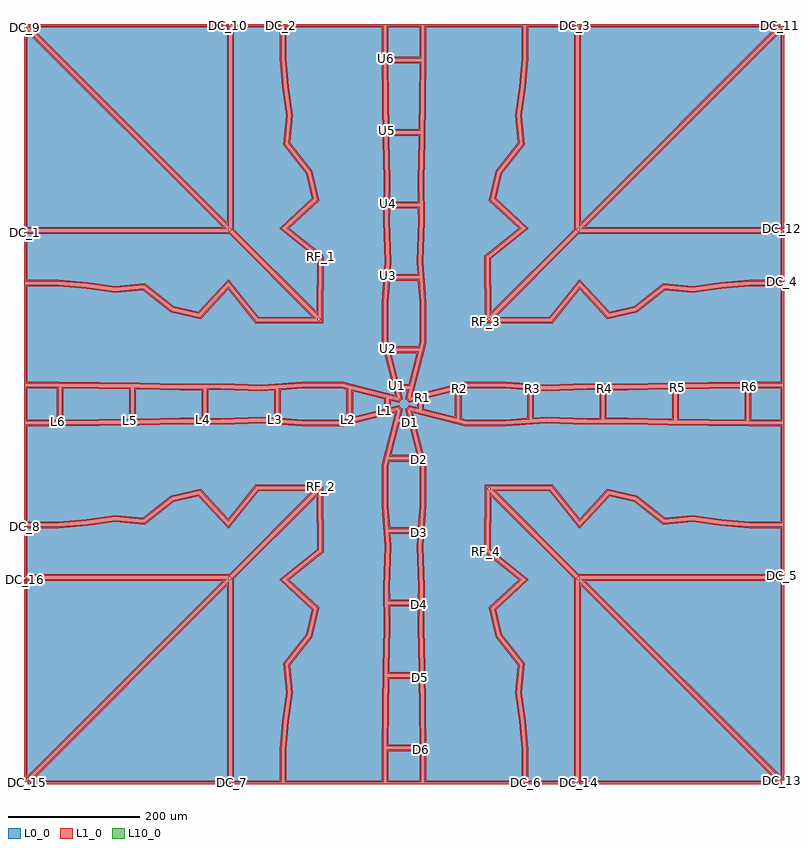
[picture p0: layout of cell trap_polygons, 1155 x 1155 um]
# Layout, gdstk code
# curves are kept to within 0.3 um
import gdstk
lib = gdstk.Library(unit=1e-6, precision=1e-09)
def P(c, l, *ps):  # polygons
    for p in ps: c.add(gdstk.Polygon(p, *l))
L0_0 = (0, 0)
L1_0 = (1, 0)
L10_0 = (10, 0)

trap_polygons = lib.new_cell('trap_polygons')
P(trap_polygons, L0_0, [(-575,-266.125),(-269.661,-266.125),(-575,-571.464),(-575,-266.125)],
  [(-571.464,-575),(-266.125,-269.661),(-266.125,-575),(-571.464,-575)],
  [(266.125,-575),(266.125,-269.661),(571.464,-575),(266.125,-575)],
  [(575,-571.464),(269.661,-266.125),(575,-266.125),(575,-571.464)],
  [(575,266.125),(269.661,266.125),(575,571.464),(575,266.125)],
  [(571.464,575),(266.125,269.661),(266.125,575),(571.464,575)],
  [(-266.125,575),(-266.125,269.661),(-571.464,575),(-266.125,575)],
  [(-575,571.464),(-269.661,266.125),(-575,266.125),(-575,571.464)],
  [(-575,-186.125),(-524.788,-186.125),(-481.472,-182.439),(-438.926,-176.757),(-394.504,-180.815),(-350.84,-146.071),(-311.781,-137.162),(-266.827,-185.634),(-221.734,-129.646),(-133.964,-130.428),(-264.661,-261.125),(-575,-261.125)],
  [(-261.125,-575),(-261.125,-264.661),(-130.428,-133.964),(-129.646,-221.734),(-185.634,-266.827),(-137.162,-311.781),(-146.071,-350.84),(-180.815,-394.504),(-176.757,-438.926),(-182.439,-481.472),(-186.125,-524.788),(-186.125,-575)],
  [(186.125,-575),(186.125,-524.788),(182.439,-481.472),(176.757,-438.926),(180.815,-394.504),(146.071,-350.84),(137.162,-311.781),(185.634,-266.827),(129.646,-221.734),(130.428,-133.964),(261.125,-264.661),(261.125,-575)],
  [(575,-261.125),(264.661,-261.125),(133.964,-130.428),(221.734,-129.646),(266.827,-185.634),(311.781,-137.162),(350.84,-146.071),(394.504,-180.815),(438.926,-176.757),(481.472,-182.439),(524.788,-186.125),(575,-186.125)],
  [(575,186.125),(524.788,186.125),(481.472,182.439),(438.926,176.757),(394.504,180.815),(350.84,146.071),(311.781,137.162),(266.827,185.634),(221.734,129.646),(133.964,130.428),(264.661,261.125),(575,261.125)],
  [(261.125,575),(261.125,264.661),(130.428,133.964),(129.646,221.734),(185.634,266.827),(137.162,311.781),(146.071,350.84),(180.815,394.504),(176.757,438.926),(182.439,481.472),(186.125,524.788),(186.125,575)],
  [(-186.125,575),(-186.125,524.788),(-182.439,481.472),(-176.757,438.926),(-180.815,394.504),(-146.071,350.84),(-137.162,311.781),(-185.634,266.827),(-129.646,221.734),(-130.428,133.964),(-261.125,264.661),(-261.125,575)],
  [(-575,261.125),(-264.661,261.125),(-133.964,130.428),(-221.734,129.646),(-266.827,185.634),(-311.781,137.162),(-350.84,146.071),(-394.504,180.815),(-438.926,176.757),(-481.472,182.439),(-524.788,186.125),(-575,186.125)],
  [(-26.125,525),(-26.125,575),(26.125,575),(26.125,525),(-26.125,525)],
  [(525,26.125),(575,26.125),(575,-26.125),(525,-26.125),(525,26.125)],
  [(26.125,-525),(26.125,-575),(-26.125,-575),(-26.125,-525),(26.125,-525)],
  [(-525,-26.125),(-575,-26.125),(-575,26.125),(-525,26.125),(-525,-26.125)],
  [(-24.813,415),(-25.435,463.528),(-26.125,520),(26.125,520),(25.435,463.528),(24.813,415),(-24.813,415)],
  [(415,24.813),(463.528,25.435),(520,26.125),(520,-26.125),(463.528,-25.435),(415,-24.813),(415,24.813)],
  [(24.813,-415),(25.435,-463.528),(26.125,-520),(-26.125,-520),(-25.435,-463.528),(-24.813,-415),(24.813,-415)],
  [(-415,-24.813),(-463.528,-25.435),(-520,-26.125),(-520,26.125),(-463.528,25.435),(-415,24.813),(-415,-24.813)],
  [(-23.661,305),(-23.354,339.827),(-24.641,401.615),(-24.749,410),(24.749,410),(24.641,401.615),(23.354,339.827),(23.661,305),(-23.661,305)],
  [(305,23.661),(339.827,23.354),(401.615,24.641),(410,24.749),(410,-24.749),(401.615,-24.641),(339.827,-23.354),(305,-23.661),(305,23.661)],
  [(23.661,-305),(23.354,-339.827),(24.641,-401.615),(24.749,-410),(-24.749,-410),(-24.641,-401.615),(-23.354,-339.827),(-23.661,-305),(23.661,-305)],
  [(-305,-23.661),(-339.827,-23.354),(-401.615,-24.641),(-410,-24.749),(-410,24.749),(-401.615,24.641),(-339.827,23.354),(-305,23.661),(-305,-23.661)],
  [(-23.237,195),(-21.725,216.238),(-23.897,278.128),(-23.705,300),(23.705,300),(23.897,278.128),(21.725,216.238),(23.237,195),(-23.237,195)],
  [(195,23.237),(216.238,21.725),(278.128,23.897),(300,23.705),(300,-23.705),(278.128,-23.897),(216.238,-21.725),(195,-23.237),(195,23.237)],
  [(23.237,-195),(21.725,-216.238),(23.897,-278.128),(23.705,-300),(-23.705,-300),(-23.897,-278.128),(-21.725,-216.238),(-23.237,-195),(23.237,-195)],
  [(-195,-23.237),(-216.238,-21.725),(-278.128,-23.897),(-300,-23.705),(-300,23.705),(-278.128,23.897),(-216.238,21.725),(-195,23.237),(-195,-23.237)],
  [(-23.931,85),(-26.091,93.487),(-26.125,154.417),(-23.592,190),(23.592,190),(26.125,154.417),(26.091,93.487),(23.931,85),(-23.931,85)],
  [(85,23.931),(93.487,26.091),(154.417,26.125),(190,23.592),(190,-23.592),(154.417,-26.125),(93.487,-26.091),(85,-23.931),(85,23.931)],
  [(23.931,-85),(26.091,-93.487),(26.125,-154.417),(23.592,-190),(-23.592,-190),(-26.125,-154.417),(-26.091,-93.487),(-23.931,-85),(23.931,-85)],
  [(-85,-23.931),(-93.487,-26.091),(-154.417,-26.125),(-190,-23.592),(-190,23.592),(-154.417,26.125),(-93.487,26.091),(-85,23.931),(-85,-23.931)],
  [(-9.299,27.5),(-22.659,80),(22.659,80),(9.299,27.5),(-9.299,27.5)],
  [(27.5,9.299),(80,22.659),(80,-22.659),(27.5,-9.299),(27.5,9.299)],
  [(9.299,-27.5),(22.659,-80),(-22.659,-80),(-9.299,-27.5),(9.299,-27.5)],
  [(-27.5,-9.299),(-80,-22.659),(-80,22.659),(-27.5,9.299),(-27.5,-9.299)],
  [(8.315,-5.556),(6.344,-7.73),(4.563,-8.89),(8.027,-22.5),(-8.027,-22.5),(-4.563,-8.89),(-7.071,-7.071),(-8.89,-4.563),(-22.5,-8.027),(-22.5,8.027),(-8.89,4.563),(-7.071,7.071),(-4.563,8.89),(-8.027,22.5),(8.027,22.5),(4.563,8.89),(7.071,7.071),(8.89,4.563),(22.5,8.027),(22.5,-8.027),(8.89,-4.563)],
  [(124.625,-224.109),(177.993,-267.094),(131.645,-310.078),(141.449,-353.062),(175.653,-396.047),(171.727,-439.031),(177.467,-482.016),(181.125,-525),(181.125,-575),(31.125,-575),(31.125,-525),(30.432,-463.266),(28.355,-339.797),(28.898,-278.062),(26.731,-216.328),(31.125,-154.594),(31.091,-92.859),(10.007,-10.007),(92.859,-31.091),(154.594,-31.125),(216.328,-26.731),(278.062,-28.898),(339.797,-28.355),(463.266,-30.432),(525,-31.125),(575,-31.125),(575,-181.125),(525,-181.125),(482.016,-177.467),(439.031,-171.727),(396.047,-175.653),(353.062,-141.449),(310.078,-131.645),(267.094,-177.993),(224.109,-124.625),(125.504,-125.504)],
  [(125.504,125.504),(224.109,124.625),(267.094,177.993),(310.078,131.645),(353.062,141.449),(396.047,175.653),(439.031,171.727),(482.016,177.467),(525,181.125),(575,181.125),(575,31.125),(525,31.125),(463.266,30.432),(339.797,28.355),(278.062,28.898),(216.328,26.731),(154.594,31.125),(92.859,31.091),(10.007,10.007),(31.091,92.859),(31.125,154.594),(26.731,216.328),(28.898,278.062),(28.355,339.797),(30.432,463.266),(31.125,525),(31.125,575),(181.125,575),(181.125,525),(177.467,482.016),(171.727,439.031),(175.653,396.047),(141.449,353.062),(131.645,310.078),(177.993,267.094),(124.625,224.109)],
  [(-125.504,-125.504),(-224.109,-124.625),(-267.094,-177.993),(-310.078,-131.645),(-353.062,-141.449),(-396.047,-175.653),(-439.031,-171.727),(-482.016,-177.467),(-525,-181.125),(-575,-181.125),(-575,-31.125),(-525,-31.125),(-463.266,-30.432),(-339.797,-28.355),(-278.062,-28.898),(-216.328,-26.731),(-154.594,-31.125),(-92.859,-31.091),(-10.007,-10.007),(-31.091,-92.859),(-31.125,-154.594),(-26.731,-216.328),(-28.898,-278.062),(-28.355,-339.797),(-30.432,-463.266),(-31.125,-525),(-31.125,-575),(-181.125,-575),(-181.125,-525),(-177.467,-482.016),(-171.727,-439.031),(-175.653,-396.047),(-141.449,-353.062),(-131.645,-310.078),(-177.993,-267.094),(-124.625,-224.109)],
  [(-124.625,224.109),(-177.993,267.094),(-131.645,310.078),(-141.449,353.062),(-175.653,396.047),(-171.727,439.031),(-177.467,482.016),(-181.125,525),(-181.125,575),(-31.125,575),(-31.125,525),(-30.432,463.266),(-28.355,339.797),(-28.898,278.062),(-26.731,216.328),(-31.125,154.594),(-31.091,92.859),(-10.007,10.007),(-92.859,31.091),(-154.594,31.125),(-216.328,26.731),(-278.062,28.898),(-339.797,28.355),(-463.266,30.432),(-525,31.125),(-575,31.125),(-575,181.125),(-525,181.125),(-482.016,177.467),(-439.031,171.727),(-396.047,175.653),(-353.062,141.449),(-310.078,131.645),(-267.094,177.993),(-224.109,124.625),(-125.504,125.504)])
P(trap_polygons, L1_0, [(-575,-263.625),(-575,-268.625),(-275.696,-268.625),(-572.5,-565.429),(-572.5,-266.125),(-577.5,-266.125),(-577.5,-573.964),(-575,-575),(-266.125,-266.125),(-267.161,-263.625)],
  [(-573.232,-573.232),(-569.697,-576.768),(-268.625,-275.696),(-268.625,-572.5),(-571.464,-572.5),(-571.464,-577.5),(-263.625,-577.5),(-263.625,-267.161),(-266.125,-266.125)],
  [(263.625,-575),(268.625,-575),(268.625,-275.696),(565.429,-572.5),(266.125,-572.5),(266.125,-577.5),(573.964,-577.5),(575,-575),(266.125,-266.125),(263.625,-267.161)],
  [(573.232,-573.232),(576.768,-569.697),(275.696,-268.625),(572.5,-268.625),(572.5,-571.464),(577.5,-571.464),(577.5,-263.625),(267.161,-263.625),(266.125,-266.125)],
  [(575,263.625),(575,268.625),(275.696,268.625),(572.5,565.429),(572.5,266.125),(577.5,266.125),(577.5,573.964),(575,575),(266.125,266.125),(267.161,263.625)],
  [(573.232,573.232),(569.697,576.768),(268.625,275.696),(268.625,572.5),(571.464,572.5),(571.464,577.5),(263.625,577.5),(263.625,267.161),(266.125,266.125)],
  [(-263.625,575),(-268.625,575),(-268.625,275.696),(-565.429,572.5),(-266.125,572.5),(-266.125,577.5),(-573.964,577.5),(-575,575),(-266.125,266.125),(-263.625,267.161)],
  [(-573.232,573.232),(-576.768,569.697),(-275.696,268.625),(-572.5,268.625),(-572.5,571.464),(-577.5,571.464),(-577.5,263.625),(-267.161,263.625),(-266.125,266.125)],
  [(-575,-183.625),(-575,-188.625),(-524.681,-188.625),(-481.201,-184.925),(-438.874,-179.272),(-393.732,-183.396),(-349.729,-148.381),(-312.632,-139.92),(-266.96,-189.167),(-266.448,-189.149),(-220.546,-132.157),(-139.946,-132.875),(-265.696,-258.625),(-572.5,-258.625),(-572.5,-186.125),(-577.5,-186.125),(-577.5,-263.625),(-263.625,-263.625),(-130.428,-130.428),(-131.442,-127.951),(-222.921,-127.136),(-266.961,-181.814),(-310.93,-134.403),(-351.951,-143.76),(-395.275,-178.234),(-438.979,-174.242),(-481.744,-179.953),(-524.894,-183.625)],
  [(-263.625,-575),(-258.625,-575),(-258.625,-265.696),(-132.875,-139.946),(-132.157,-220.546),(-189.149,-266.448),(-189.167,-266.96),(-139.92,-312.632),(-148.381,-349.729),(-183.396,-393.732),(-179.272,-438.874),(-184.925,-481.201),(-188.625,-524.681),(-188.625,-572.5),(-261.125,-572.5),(-261.125,-577.5),(-183.625,-577.5),(-183.625,-524.894),(-179.953,-481.744),(-174.242,-438.979),(-178.234,-395.275),(-143.76,-351.951),(-134.403,-310.93),(-181.814,-266.961),(-127.136,-222.921),(-127.951,-131.442),(-130.428,-130.428),(-263.625,-263.625)],
  [(183.625,-575),(188.625,-575),(188.625,-524.681),(184.925,-481.201),(179.272,-438.874),(183.396,-393.732),(148.381,-349.729),(139.92,-312.632),(189.167,-266.96),(189.149,-266.448),(132.157,-220.546),(132.875,-139.946),(258.625,-265.696),(258.625,-572.5),(186.125,-572.5),(186.125,-577.5),(263.625,-577.5),(263.625,-263.625),(130.428,-130.428),(127.951,-131.442),(127.136,-222.921),(181.814,-266.961),(134.403,-310.93),(143.76,-351.951),(178.234,-395.275),(174.242,-438.979),(179.953,-481.744),(183.625,-524.894)],
  [(575,-263.625),(575,-258.625),(265.696,-258.625),(139.946,-132.875),(220.546,-132.157),(266.448,-189.149),(266.96,-189.167),(312.632,-139.92),(349.729,-148.381),(393.732,-183.396),(438.874,-179.272),(481.201,-184.925),(524.681,-188.625),(572.5,-188.625),(572.5,-261.125),(577.5,-261.125),(577.5,-183.625),(524.894,-183.625),(481.744,-179.953),(438.979,-174.242),(395.275,-178.234),(351.951,-143.76),(310.93,-134.403),(266.961,-181.814),(222.921,-127.136),(131.442,-127.951),(130.428,-130.428),(263.625,-263.625)],
  [(575,183.625),(575,188.625),(524.681,188.625),(481.201,184.925),(438.874,179.272),(393.732,183.396),(349.729,148.381),(312.632,139.92),(266.96,189.167),(266.448,189.149),(220.546,132.157),(139.946,132.875),(265.696,258.625),(572.5,258.625),(572.5,186.125),(577.5,186.125),(577.5,263.625),(263.625,263.625),(130.428,130.428),(131.442,127.951),(222.921,127.136),(266.961,181.814),(310.93,134.403),(351.951,143.76),(395.275,178.234),(438.979,174.242),(481.744,179.953),(524.894,183.625)],
  [(263.625,575),(258.625,575),(258.625,265.696),(132.875,139.946),(132.157,220.546),(189.149,266.448),(189.167,266.96),(139.92,312.632),(148.381,349.729),(183.396,393.732),(179.272,438.874),(184.925,481.201),(188.625,524.681),(188.625,572.5),(261.125,572.5),(261.125,577.5),(183.625,577.5),(183.625,524.894),(179.953,481.744),(174.242,438.979),(178.234,395.275),(143.76,351.951),(134.403,310.93),(181.814,266.961),(127.136,222.921),(127.951,131.442),(130.428,130.428),(263.625,263.625)],
  [(-183.625,575),(-188.625,575),(-188.625,524.681),(-184.925,481.201),(-179.272,438.874),(-183.396,393.732),(-148.381,349.729),(-139.92,312.632),(-189.167,266.96),(-189.149,266.448),(-132.157,220.546),(-132.875,139.946),(-258.625,265.696),(-258.625,572.5),(-186.125,572.5),(-186.125,577.5),(-263.625,577.5),(-263.625,263.625),(-130.428,130.428),(-127.951,131.442),(-127.136,222.921),(-181.814,266.961),(-134.403,310.93),(-143.76,351.951),(-178.234,395.275),(-174.242,438.979),(-179.953,481.744),(-183.625,524.894)],
  [(-575,263.625),(-575,258.625),(-265.696,258.625),(-139.946,132.875),(-220.546,132.157),(-266.448,189.149),(-266.96,189.167),(-312.632,139.92),(-349.729,148.381),(-393.732,183.396),(-438.874,179.272),(-481.201,184.925),(-524.681,188.625),(-572.5,188.625),(-572.5,261.125),(-577.5,261.125),(-577.5,183.625),(-524.894,183.625),(-481.744,179.953),(-438.979,174.242),(-395.275,178.234),(-351.951,143.76),(-310.93,134.403),(-266.961,181.814),(-222.921,127.136),(-131.442,127.951),(-130.428,130.428),(-263.625,263.625)],
  [(-28.625,525),(-23.625,525),(-23.625,572.5),(23.625,572.5),(23.625,527.5),(-26.125,527.5),(-26.125,522.5),(28.625,522.5),(28.625,577.5),(-28.625,577.5)],
  [(525,28.625),(525,23.625),(572.5,23.625),(572.5,-23.625),(527.5,-23.625),(527.5,26.125),(522.5,26.125),(522.5,-28.625),(577.5,-28.625),(577.5,28.625)],
  [(28.625,-525),(23.625,-525),(23.625,-572.5),(-23.625,-572.5),(-23.625,-527.5),(26.125,-527.5),(26.125,-522.5),(-28.625,-522.5),(-28.625,-577.5),(28.625,-577.5)],
  [(-525,-28.625),(-525,-23.625),(-572.5,-23.625),(-572.5,23.625),(-527.5,23.625),(-527.5,-26.125),(-522.5,-26.125),(-522.5,28.625),(-577.5,28.625),(-577.5,-28.625)],
  [(-27.313,414.968),(-22.313,415.032),(-23.594,517.5),(23.594,517.5),(22.345,417.5),(-24.813,417.5),(-24.813,412.5),(27.281,412.5),(28.625,522.5),(-28.655,522.469)],
  [(414.968,27.313),(415.032,22.313),(517.5,23.594),(517.5,-23.594),(417.5,-22.345),(417.5,24.813),(412.5,24.813),(412.5,-27.281),(522.5,-28.625),(522.469,28.655)],
  [(27.313,-414.968),(22.313,-415.032),(23.594,-517.5),(-23.594,-517.5),(-22.345,-417.5),(24.813,-417.5),(24.813,-412.5),(-27.281,-412.5),(-28.625,-522.5),(28.655,-522.469)],
  [(-414.968,-27.313),(-415.032,-22.313),(-517.5,-23.594),(-517.5,23.594),(-417.5,22.345),(-417.5,-24.813),(-412.5,-24.813),(-412.5,27.281),(-522.5,28.625),(-522.469,-28.655)],
  [(-26.161,305.022),(-21.161,304.978),(-20.854,339.842),(-22.216,407.5),(22.216,407.5),(20.854,339.842),(21.139,307.5),(-23.661,307.5),(-23.661,302.5),(26.183,302.522),(25.855,339.812),(27.249,412.5),(-27.281,412.468),(-25.855,339.812)],
  [(305.022,26.161),(304.978,21.161),(339.842,20.854),(407.5,22.216),(407.5,-22.216),(339.842,-20.854),(307.5,-21.139),(307.5,23.661),(302.5,23.661),(302.522,-26.183),(339.812,-25.855),(412.5,-27.249),(412.468,27.281),(339.812,25.855)],
  [(26.161,-305.022),(21.161,-304.978),(20.854,-339.842),(22.216,-407.5),(-22.216,-407.5),(-20.854,-339.842),(-21.139,-307.5),(23.661,-307.5),(23.661,-302.5),(-26.183,-302.522),(-25.855,-339.812),(-27.249,-412.5),(27.281,-412.468),(25.855,-339.812)],
  [(-305.022,-26.161),(-304.978,-21.161),(-339.842,-20.854),(-407.5,-22.216),(-407.5,22.216),(-339.842,20.854),(-307.5,21.139),(-307.5,-23.661),(-302.5,-23.661),(-302.522,26.183),(-339.812,25.855),(-412.5,27.249),(-412.468,-27.281),(-339.812,-25.855)],
  [(-25.73,195.177),(-20.743,194.823),(-19.222,216.193),(-21.397,278.161),(-21.227,297.5),(21.227,297.5),(21.397,278.161),(19.222,216.193),(20.552,197.5),(-23.237,197.5),(-23.237,192.5),(25.908,192.684),(24.228,216.283),(26.397,278.095),(26.183,302.5),(-26.183,302.5),(-26.397,278.095),(-24.228,216.283)],
  [(195.177,25.73),(194.823,20.743),(216.193,19.222),(278.161,21.397),(297.5,21.227),(297.5,-21.227),(278.161,-21.397),(216.193,-19.222),(197.5,-20.552),(197.5,23.237),(192.5,23.237),(192.684,-25.908),(216.283,-24.228),(278.095,-26.397),(302.5,-26.183),(302.5,26.183),(278.095,26.397),(216.283,24.228)],
  [(25.73,-195.177),(20.743,-194.823),(19.222,-216.193),(21.397,-278.161),(21.227,-297.5),(-21.227,-297.5),(-21.397,-278.161),(-19.222,-216.193),(-20.552,-197.5),(23.237,-197.5),(23.237,-192.5),(-25.908,-192.684),(-24.228,-216.283),(-26.397,-278.095),(-26.183,-302.5),(26.183,-302.5),(26.397,-278.095),(24.228,-216.283)],
  [(-195.177,-25.73),(-194.823,-20.743),(-216.193,-19.222),(-278.161,-21.397),(-297.5,-21.227),(-297.5,21.227),(-278.161,21.397),(-216.193,19.222),(-197.5,20.552),(-197.5,-23.237),(-192.5,-23.237),(-192.684,25.908),(-216.283,24.228),(-278.095,26.397),(-302.5,26.183),(-302.5,-26.183),(-278.095,-26.397),(-216.283,-24.228)],
  [(-26.354,84.383),(-21.509,85.617),(-23.591,93.801),(-23.625,154.329),(-21.264,187.5),(21.264,187.5),(23.625,154.329),(23.591,93.801),(21.988,87.5),(-23.931,87.5),(-23.931,82.5),(25.875,82.5),(28.591,93.173),(28.625,154.506),(25.921,192.5),(-25.921,192.5),(-28.625,154.506),(-28.591,93.173)],
  [(84.383,26.354),(85.617,21.509),(93.801,23.591),(154.329,23.625),(187.5,21.264),(187.5,-21.264),(154.329,-23.625),(93.801,-23.591),(87.5,-21.988),(87.5,23.931),(82.5,23.931),(82.5,-25.875),(93.173,-28.591),(154.506,-28.625),(192.5,-25.921),(192.5,25.921),(154.506,28.625),(93.173,28.591)],
  [(26.354,-84.383),(21.509,-85.617),(23.591,-93.801),(23.625,-154.329),(21.264,-187.5),(-21.264,-187.5),(-23.625,-154.329),(-23.591,-93.801),(-21.988,-87.5),(23.931,-87.5),(23.931,-82.5),(-25.875,-82.5),(-28.591,-93.173),(-28.625,-154.506),(-25.921,-192.5),(25.921,-192.5),(28.625,-154.506),(28.591,-93.173)],
  [(-84.383,-26.354),(-85.617,-21.509),(-93.801,-23.591),(-154.329,-23.625),(-187.5,-21.264),(-187.5,21.264),(-154.329,23.625),(-93.801,23.591),(-87.5,21.988),(-87.5,-23.931),(-82.5,-23.931),(-82.5,25.875),(-93.173,28.591),(-154.506,28.625),(-192.5,25.921),(-192.5,-25.921),(-154.506,-28.625),(-93.173,-28.591)],
  [(-11.722,26.883),(-6.876,28.117),(-19.443,77.5),(19.443,77.5),(7.356,30),(-9.299,30),(-9.299,25),(11.243,25),(25.698,81.806),(25.159,82.5),(-25.159,82.5),(-25.698,81.806)],
  [(26.883,11.722),(28.117,6.876),(77.5,19.443),(77.5,-19.443),(30,-7.356),(30,9.299),(25,9.299),(25,-11.243),(81.806,-25.698),(82.5,-25.159),(82.5,25.159),(81.806,25.698)],
  [(11.722,-26.883),(6.876,-28.117),(19.443,-77.5),(-19.443,-77.5),(-7.356,-30),(9.299,-30),(9.299,-25),(-11.243,-25),(-25.698,-81.806),(-25.159,-82.5),(25.159,-82.5),(25.698,-81.806)],
  [(-26.883,-11.722),(-28.117,-6.876),(-77.5,-19.443),(-77.5,19.443),(-30,7.356),(-30,-9.299),(-25,-9.299),(-25,11.243),(-81.806,25.698),(-82.5,25.159),(-82.5,-25.159),(-81.806,-25.698)],
  [(10.323,-7.045),(6.307,-4.066),(4.165,-6.234),(1.633,-7.511),(4.811,-20),(-4.811,-20),(-1.633,-7.511),(-5.301,-5.301),(-7.511,-1.633),(-20,-4.811),(-20,4.811),(-7.511,1.633),(-5.301,5.301),(-1.633,7.511),(-4.811,20),(4.811,20),(1.633,7.511),(5.301,5.301),(7.511,1.633),(20,4.811),(20,-4.811),(7.511,-1.633),(6.17,-4.27),(10.459,-6.841),(11.027,-5.894),(10.27,-7.494),(24.306,-11.066),(25,-10.527),(25,10.527),(24.306,11.066),(10.27,7.494),(11.027,5.894),(8.841,8.841),(5.894,11.027),(7.494,10.27),(11.066,24.306),(10.527,25),(-10.527,25),(-11.066,24.306),(-7.494,10.27),(-5.894,11.027),(-8.841,8.841),(-11.027,5.894),(-10.27,7.494),(-24.306,11.066),(-25,10.527),(-25,-10.527),(-24.306,-11.066),(-10.27,-7.494),(-11.027,-5.894),(-8.841,-8.841),(-5.894,-11.027),(-7.494,-10.27),(-11.066,-24.306),(-10.527,-25),(10.527,-25),(11.066,-24.306),(7.494,-10.27),(5.894,-11.027),(7.932,-9.665)],
  [(126.193,-222.162),(123.057,-226.056),(174.173,-267.227),(128.887,-309.227),(139.138,-354.174),(173.072,-396.819),(169.212,-439.084),(174.981,-482.287),(178.625,-525.106),(178.625,-572.5),(33.625,-572.5),(33.625,-524.986),(32.932,-463.236),(30.855,-339.782),(31.398,-278.03),(29.234,-216.373),(33.625,-154.682),(33.591,-92.546),(13.467,-13.467),(92.546,-33.591),(154.682,-33.625),(216.373,-29.234),(278.03,-31.398),(339.782,-30.855),(463.236,-32.932),(524.986,-33.625),(572.5,-33.625),(572.5,-178.625),(525.106,-178.625),(482.287,-174.981),(439.084,-169.212),(396.819,-173.072),(354.174,-139.138),(309.227,-128.887),(267.227,-174.173),(225.297,-122.114),(123.026,-123.026),(122.125,-224.087),(127.125,-224.132),(127.982,-127.982),(222.921,-127.136),(266.715,-181.509),(267.227,-181.526),(310.93,-134.403),(351.951,-143.76),(395.275,-178.234),(438.979,-174.242),(481.744,-179.953),(524.894,-183.625),(577.5,-183.625),(577.5,-28.625),(525.014,-28.625),(463.296,-27.933),(339.812,-25.855),(278.095,-26.397),(216.283,-24.228),(154.506,-28.625),(93.173,-28.591),(8.201,-6.968),(6.968,-8.201),(28.591,-93.173),(28.625,-154.506),(24.228,-216.283),(26.397,-278.095),(25.855,-339.812),(27.933,-463.296),(28.625,-525.014),(28.625,-577.5),(183.625,-577.5),(183.625,-524.894),(179.953,-481.744),(174.242,-438.979),(178.234,-395.275),(143.76,-351.951),(134.403,-310.93),(181.526,-267.227),(181.509,-266.715)],
  [(125.526,128.004),(125.481,123.004),(225.297,122.114),(267.227,174.173),(309.227,128.887),(354.174,139.138),(396.819,173.072),(439.084,169.212),(482.287,174.981),(525.106,178.625),(572.5,178.625),(572.5,33.625),(524.986,33.625),(463.236,32.932),(339.782,30.855),(278.03,31.398),(216.373,29.234),(154.682,33.625),(92.546,33.591),(13.467,13.467),(33.591,92.546),(33.625,154.682),(29.234,216.373),(31.398,278.03),(30.855,339.782),(32.932,463.236),(33.625,524.986),(33.625,572.5),(178.625,572.5),(178.625,525.106),(174.981,482.287),(169.212,439.084),(173.072,396.819),(139.138,354.174),(128.887,309.227),(174.173,267.227),(122.114,225.297),(123.004,125.481),(128.004,125.526),(127.136,222.921),(181.509,266.715),(181.526,267.227),(134.403,310.93),(143.76,351.951),(178.234,395.275),(174.242,438.979),(179.953,481.744),(183.625,524.894),(183.625,577.5),(28.625,577.5),(28.625,525.014),(27.933,463.296),(25.855,339.812),(26.397,278.095),(24.228,216.283),(28.625,154.506),(28.591,93.173),(6.968,8.201),(8.201,6.968),(93.173,28.591),(154.506,28.625),(216.283,24.228),(278.095,26.397),(339.812,25.855),(463.296,27.933),(525.014,28.625),(577.5,28.625),(577.5,183.625),(524.894,183.625),(481.744,179.953),(438.979,174.242),(395.275,178.234),(351.951,143.76),(310.93,134.403),(267.227,181.526),(266.715,181.509),(222.921,127.136)],
  [(-125.526,-128.004),(-125.481,-123.004),(-225.297,-122.114),(-267.227,-174.173),(-309.227,-128.887),(-354.174,-139.138),(-396.819,-173.072),(-439.084,-169.212),(-482.287,-174.981),(-525.106,-178.625),(-572.5,-178.625),(-572.5,-33.625),(-524.986,-33.625),(-463.236,-32.932),(-339.782,-30.855),(-278.03,-31.398),(-216.373,-29.234),(-154.682,-33.625),(-92.546,-33.591),(-13.467,-13.467),(-33.591,-92.546),(-33.625,-154.682),(-29.234,-216.373),(-31.398,-278.03),(-30.855,-339.782),(-32.932,-463.236),(-33.625,-524.986),(-33.625,-572.5),(-178.625,-572.5),(-178.625,-525.106),(-174.981,-482.287),(-169.212,-439.084),(-173.072,-396.819),(-139.138,-354.174),(-128.887,-309.227),(-174.173,-267.227),(-122.114,-225.297),(-123.004,-125.481),(-128.004,-125.526),(-127.136,-222.921),(-181.509,-266.715),(-181.526,-267.227),(-134.403,-310.93),(-143.76,-351.951),(-178.234,-395.275),(-174.242,-438.979),(-179.953,-481.744),(-183.625,-524.894),(-183.625,-577.5),(-28.625,-577.5),(-28.625,-525.014),(-27.933,-463.296),(-25.855,-339.812),(-26.397,-278.095),(-24.228,-216.283),(-28.625,-154.506),(-28.591,-93.173),(-6.968,-8.201),(-8.201,-6.968),(-93.173,-28.591),(-154.506,-28.625),(-216.283,-24.228),(-278.095,-26.397),(-339.812,-25.855),(-463.296,-27.933),(-525.014,-28.625),(-577.5,-28.625),(-577.5,-183.625),(-524.894,-183.625),(-481.744,-179.953),(-438.979,-174.242),(-395.275,-178.234),(-351.951,-143.76),(-310.93,-134.403),(-267.227,-181.526),(-266.715,-181.509),(-222.921,-127.136)],
  [(-126.193,222.162),(-123.057,226.056),(-174.173,267.227),(-128.887,309.227),(-139.138,354.174),(-173.072,396.819),(-169.212,439.084),(-174.981,482.287),(-178.625,525.106),(-178.625,572.5),(-33.625,572.5),(-33.625,524.986),(-32.932,463.236),(-30.855,339.782),(-31.398,278.03),(-29.234,216.373),(-33.625,154.682),(-33.591,92.546),(-13.467,13.467),(-92.546,33.591),(-154.682,33.625),(-216.373,29.234),(-278.03,31.398),(-339.782,30.855),(-463.236,32.932),(-524.986,33.625),(-572.5,33.625),(-572.5,178.625),(-525.106,178.625),(-482.287,174.981),(-439.084,169.212),(-396.819,173.072),(-354.174,139.138),(-309.227,128.887),(-267.227,174.173),(-225.297,122.114),(-123.026,123.026),(-122.125,224.087),(-127.125,224.132),(-127.982,127.982),(-222.921,127.136),(-266.715,181.509),(-267.227,181.526),(-310.93,134.403),(-351.951,143.76),(-395.275,178.234),(-438.979,174.242),(-481.744,179.953),(-524.894,183.625),(-577.5,183.625),(-577.5,28.625),(-525.014,28.625),(-463.296,27.933),(-339.812,25.855),(-278.095,26.397),(-216.283,24.228),(-154.506,28.625),(-93.173,28.591),(-8.201,6.968),(-6.968,8.201),(-28.591,93.173),(-28.625,154.506),(-24.228,216.283),(-26.397,278.095),(-25.855,339.812),(-27.933,463.296),(-28.625,525.014),(-28.625,577.5),(-183.625,577.5),(-183.625,524.894),(-179.953,481.744),(-174.242,438.979),(-178.234,395.275),(-143.76,351.951),(-134.403,310.93),(-181.526,267.227),(-181.509,266.715)])
P(trap_polygons, L10_0, [(0,0),(0,0),(0,0),(0,0)])
trap_polygons.add(gdstk.Label('DC_16', (-575,-266.125), layer=2, texttype=0))
trap_polygons.add(gdstk.Label('DC_15', (-571.464,-575), layer=2, texttype=0))
trap_polygons.add(gdstk.Label('DC_14', (266.125,-575), layer=2, texttype=0))
trap_polygons.add(gdstk.Label('DC_13', (575,-571.464), layer=2, texttype=0))
trap_polygons.add(gdstk.Label('DC_12', (575,266.125), layer=2, texttype=0))
trap_polygons.add(gdstk.Label('DC_11', (571.464,575), layer=2, texttype=0))
trap_polygons.add(gdstk.Label('DC_10', (-266.125,575), layer=2, texttype=0))
trap_polygons.add(gdstk.Label('DC_9', (-575,571.464), layer=2, texttype=0))
trap_polygons.add(gdstk.Label('DC_8', (-575,-186.125), layer=2, texttype=0))
trap_polygons.add(gdstk.Label('DC_7', (-261.125,-575), layer=2, texttype=0))
trap_polygons.add(gdstk.Label('DC_6', (186.125,-575), layer=2, texttype=0))
trap_polygons.add(gdstk.Label('DC_5', (575,-261.125), layer=2, texttype=0))
trap_polygons.add(gdstk.Label('DC_4', (575,186.125), layer=2, texttype=0))
trap_polygons.add(gdstk.Label('DC_3', (261.125,575), layer=2, texttype=0))
trap_polygons.add(gdstk.Label('DC_2', (-186.125,575), layer=2, texttype=0))
trap_polygons.add(gdstk.Label('DC_1', (-575,261.125), layer=2, texttype=0))
trap_polygons.add(gdstk.Label('U6', (-26.125,525), layer=2, texttype=0))
trap_polygons.add(gdstk.Label('R6', (525,26.125), layer=2, texttype=0))
trap_polygons.add(gdstk.Label('D6', (26.125,-525), layer=2, texttype=0))
trap_polygons.add(gdstk.Label('L6', (-525,-26.125), layer=2, texttype=0))
trap_polygons.add(gdstk.Label('U5', (-24.813,415), layer=2, texttype=0))
trap_polygons.add(gdstk.Label('R5', (415,24.813), layer=2, texttype=0))
trap_polygons.add(gdstk.Label('D5', (24.813,-415), layer=2, texttype=0))
trap_polygons.add(gdstk.Label('L5', (-415,-24.813), layer=2, texttype=0))
trap_polygons.add(gdstk.Label('U4', (-23.661,305), layer=2, texttype=0))
trap_polygons.add(gdstk.Label('R4', (305,23.661), layer=2, texttype=0))
trap_polygons.add(gdstk.Label('D4', (23.661,-305), layer=2, texttype=0))
trap_polygons.add(gdstk.Label('L4', (-305,-23.661), layer=2, texttype=0))
trap_polygons.add(gdstk.Label('U3', (-23.237,195), layer=2, texttype=0))
trap_polygons.add(gdstk.Label('R3', (195,23.237), layer=2, texttype=0))
trap_polygons.add(gdstk.Label('D3', (23.237,-195), layer=2, texttype=0))
trap_polygons.add(gdstk.Label('L3', (-195,-23.237), layer=2, texttype=0))
trap_polygons.add(gdstk.Label('U2', (-23.931,85), layer=2, texttype=0))
trap_polygons.add(gdstk.Label('R2', (85,23.931), layer=2, texttype=0))
trap_polygons.add(gdstk.Label('D2', (23.931,-85), layer=2, texttype=0))
trap_polygons.add(gdstk.Label('L2', (-85,-23.931), layer=2, texttype=0))
trap_polygons.add(gdstk.Label('U1', (-9.299,27.5), layer=2, texttype=0))
trap_polygons.add(gdstk.Label('R1', (27.5,9.299), layer=2, texttype=0))
trap_polygons.add(gdstk.Label('D1', (9.299,-27.5), layer=2, texttype=0))
trap_polygons.add(gdstk.Label('L1', (-27.5,-9.299), layer=2, texttype=0))
trap_polygons.add(gdstk.Label('C', (8.315,-5.556), layer=2, texttype=0))
trap_polygons.add(gdstk.Label('RF_4', (124.625,-224.109), layer=2, texttype=0))
trap_polygons.add(gdstk.Label('RF_3', (125.504,125.504), layer=2, texttype=0))
trap_polygons.add(gdstk.Label('RF_2', (-125.504,-125.504), layer=2, texttype=0))
trap_polygons.add(gdstk.Label('RF_1', (-124.625,224.109), layer=2, texttype=0))

lib.write_gds('trap_polygons.gds')
